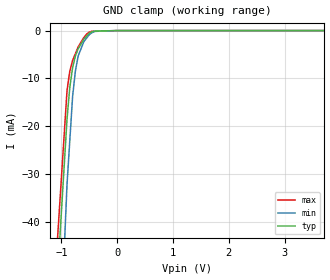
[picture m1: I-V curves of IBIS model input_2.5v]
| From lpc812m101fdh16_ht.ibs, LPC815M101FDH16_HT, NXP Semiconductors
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[Model] input_2.5v
Model_type Input
Vinl = 750.000mV
Vinh = 1.75000V
C_comp 909.000fF 904.000fF 914.000fF
| variable typ   min   max
[Voltage Range] 2.50000V 2.25000V 2.75000V
[POWER Clamp Reference] 2.50000V 2.25000V 2.75000V
[GND Clamp Reference] 0.00000V 0.00000V 0.00000V
[Temperature Range]   25   105   -40
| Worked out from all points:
|   GND clamp passes 1 mA (typ) near -0.54 V on its own axis
[GND Clamp]
-2.5V     -327.3mA   -468.3mA   -303.5mA
-900mV    -18.53mA   -32.17mA   -12.56mA
-850mV    -11.85mA   -22.98mA   -8.473mA
-800mV    -7.74mA    -13.78mA   -6.254mA
-750mV    -5.325mA   -8.465mA   -4.829mA
-700mV    -3.812mA   -5.309mA   -3.403mA
-600mV    -1.827mA   -2.349mA   -1.457mA
-550mV    -1.183mA   -1.595mA   -748.6uA
-500mV    -537.7uA   -841.1uA   -319uA
-400mV    -100.7uA   -173uA     -124uA
0V        0A         0A         0A
5V        0A         0A         0A
[POWER Clamp]
-2.5V     0A         0A         0A
5V        0A         0A         0A
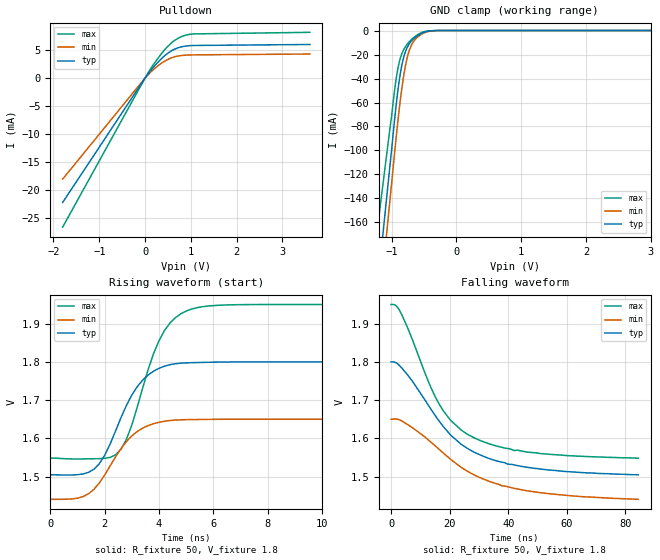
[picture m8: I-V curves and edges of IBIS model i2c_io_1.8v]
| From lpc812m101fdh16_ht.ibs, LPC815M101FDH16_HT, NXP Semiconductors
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[Model]   i2c_io_1.8v
Model_type I/O_open_drain
Vinl=5.400E-01
Vinh=1.260E+00
Vref=1.800E+00
Rref=1.000E+03
Cref=0.000E+00
Vmeas=9.000E-01
C_comp   1.060E-12   9.990E-13   1.120E-12
[Voltage Range]   1.800E+00   1.650E+00   1.950E+00
[POWER Clamp Reference]   1.800E+00   1.650E+00   1.950E+00
[GND Clamp Reference]   0.000E+00   0.000E+00   0.000E+00
[Pullup Reference]   1.800E+00   1.650E+00   1.950E+00
[Pulldown Reference]   0.000E+00   0.000E+00   0.000E+00
[Temperature Range]   25   105   -40
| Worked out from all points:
|   slope of the pulldown table from 0 to 0.27 V, typ, clamps not added: 98.8 ohm
|   GND clamp passes 1 mA (typ) near -0.47 V on its own axis
|   rising waveform, R_fixture 50, V_fixture 1.8: 20-80 % time 1.21ns typ, 1.23ns min, 1.14ns max; typ from 1.5 V to 1.8 V
|   falling waveform, R_fixture 50, V_fixture 1.8: 20-80 % time 20.3ns typ, 24.8ns min, 16.3ns max; typ from 1.8 V to 1.5 V
[GND Clamp]
-1.8V     -519.6mA   -563.5mA   -415.2mA
-1.02V    -109.2mA   -137.9mA   -78.79mA
-940mV    -66.79mA   -94.14mA   -43.75mA
-900mV    -48.42mA   -73.59mA   -30.61mA
-860mV    -33.9mA    -55.2mA    -21.96mA
-800mV    -19.64mA   -33.09mA   -14.6mA
-760mV    -14.12mA   -22.67mA   -11.43mA
-700mV    -9.08mA    -12.83mA   -7.792mA
-640mV    -5.959mA   -7.675mA   -5.035mA
-560mV    -2.946mA   -3.834mA   -2.215mA
-280mV    0A         0A         0A
3.6V      0A         0A         0A
[Pulldown]
-1.8V     -22.3mA    -18.12mA   -26.72mA
20mV      229.7uA    181.9uA    281.2uA
180mV     1.925mA    1.5mA      2.384mA
360mV     3.492mA    2.67mA     4.395mA
480mV     4.341mA    3.271mA    5.534mA
600mV     4.992mA    3.699mA    6.458mA
800mV     5.611mA    4.048mA    7.447mA
1.06V     5.842mA    4.156mA    7.913mA
3.6V      6.016mA    4.309mA    8.197mA
[Rising Waveform]
R_fixture = 50
V_fixture = 1.8
V_fixture_min = 1.65
V_fixture_max = 1.95
0s        1.505V     1.441V     1.548V
1ns       1.505V     1.444V     1.546V
1.6ns     1.519V     1.467V     1.547V
2ns       1.556V     1.504V     1.548V
2.6ns     1.654V     1.573V     1.572V
3.2ns     1.735V     1.618V     1.682V
4ns       1.783V     1.642V     1.856V
4.6ns     1.795V     1.648V     1.915V
5.2ns     1.798V     1.649V     1.938V
16.4ns    1.8V       1.65V      1.95V
[Falling Waveform]
R_fixture = 50
V_fixture = 1.8
V_fixture_min = 1.65
V_fixture_max = 1.95
0s        1.8V       1.65V      1.95V
1.8ns     1.797V     1.651V     1.946V
3.6ns     1.785V     1.646V     1.924V
13ns      1.683V     1.594V     1.744V
16.6ns    1.643V     1.57V      1.687V
20.6ns    1.607V     1.544V     1.645V
25.8ns    1.575V     1.515V     1.612V
33.6ns    1.547V     1.487V     1.586V
42ns      1.531V     1.47V      1.568V
84.4ns    1.505V     1.441V     1.548V
[Ramp]
dV/dt_r   1.7711E-01/1.1990E-09   1.2559E-01/1.2320E-09   2.4097E-01/1.1310E-09
dV/dt_f   1.7711E-01/2.0316E-08   1.2559E-01/2.4662E-08   2.4097E-01/1.6172E-08
R_load = 50
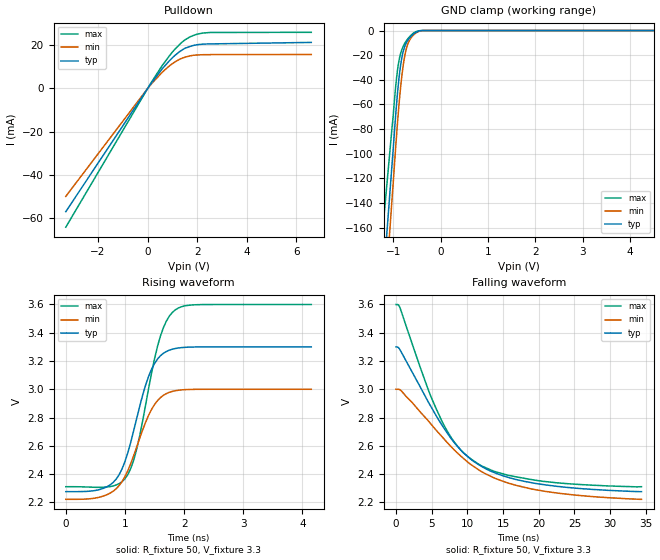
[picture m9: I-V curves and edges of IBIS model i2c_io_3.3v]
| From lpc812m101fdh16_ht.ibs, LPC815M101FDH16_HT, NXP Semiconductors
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[Model]   i2c_io_3.3v
Model_type I/O_open_drain
Vinl=9.900E-01
Vinh=2.310E+00
Vref=3.300E+00
Rref=1.000E+03
Cref=0.000E+00
Vmeas=1.650E+00
C_comp   1.060E-12   9.990E-13   1.120E-12
[Voltage Range]   3.300E+00   3.000E+00   3.600E+00
[POWER Clamp Reference]   3.300E+00   3.000E+00   3.600E+00
[GND Clamp Reference]   0.000E+00   0.000E+00   0.000E+00
[Pullup Reference]   3.300E+00   3.000E+00   3.600E+00
[Pulldown Reference]   0.000E+00   0.000E+00   0.000E+00
[Temperature Range]   25   105   -40
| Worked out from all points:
|   slope of the pulldown table from 0 to 0.495 V, typ, clamps not added: 64 ohm
|   GND clamp passes 1 mA (typ) near -0.50 V on its own axis
|   rising waveform, R_fixture 50, V_fixture 3.3: 20-80 % time 411ps typ, 441ps min, 383ps max; typ from 2.28 V to 3.3 V
|   falling waveform, R_fixture 50, V_fixture 3.3: 20-80 % time 8.61ns typ, 10.3ns min, 6.98ns max; typ from 3.3 V to 2.28 V
[GND Clamp]
-3.3V     -1.272A    -1.374A    -1.043A
-1.02V    -106.2mA   -134.5mA   -76.92mA
-940mV    -64.97mA   -90.81mA   -42.49mA
-900mV    -47.07mA   -70.46mA   -29.59mA
-840mV    -27.19mA   -44.76mA   -18.14mA
-780mV    -15.75mA   -26.03mA   -12.16mA
-740mV    -11.34mA   -17.58mA   -9.414mA
-680mV    -7.232mA   -9.814mA   -6.185mA
-620mV    -4.56mA    -5.746mA   -3.706mA
-520mV    -1.426mA   -1.973mA   -922uA
-380mV    0A         0A         0A
6.6V      0A         0A         0A
[Pulldown]
-3.3V     -57.19mA   -50.1mA    -64.4mA
140mV     2.326mA    1.953mA    2.677mA
560mV     8.72mA     7.204mA    10.16mA
920mV     13.36mA    10.86mA    15.8mA
1.1V      15.38mA    12.32mA    18.22mA
1.48V     18.52mA    14.45mA    22.35mA
1.7V      19.47mA    15.11mA    23.91mA
2V        20.34mA    15.58mA    25.25mA
2.54V     20.71mA    15.73mA    26.03mA
6.6V      21.4mA     15.79mA    26.09mA
[Rising Waveform]
R_fixture = 50
V_fixture = 3.3
V_fixture_min = 3
V_fixture_max = 3.6
0s        2.276V     2.221V     2.31V
750ps     2.324V     2.265V     2.311V
900ps     2.394V     2.317V     2.332V
1.05ns    2.553V     2.426V     2.397V
1.2ns     2.796V     2.593V     2.579V
1.45ns    3.142V     2.858V     3.116V
1.65ns    3.255V     2.957V     3.436V
1.85ns    3.288V     2.99V      3.562V
2.2ns     3.299V     2.999V     3.598V
4.15ns    3.3V       3V         3.6V
[Falling Waveform]
R_fixture = 50
V_fixture = 3.3
V_fixture_min = 3
V_fixture_max = 3.6
0s        3.3V       3V         3.6V
550ps     3.281V     2.997V     3.579V
4.5ns     2.912V     2.778V     3V
6.45ns    2.745V     2.664V     2.773V
8.25ns    2.617V     2.567V     2.621V
10.3ns    2.513V     2.475V     2.514V
13.7ns    2.412V     2.374V     2.42V
18.1ns    2.347V     2.305V     2.369V
24.65ns   2.302V     2.253V     2.33V
34.4ns    2.276V     2.221V     2.31V
[Ramp]
dV/dt_r   6.1467E-01/4.0990E-10   4.6738E-01/4.3930E-10   7.7377E-01/3.8130E-10
dV/dt_f   6.1467E-01/8.5863E-09   4.6738E-01/1.0265E-08   7.7377E-01/6.9793E-09
R_load = 50
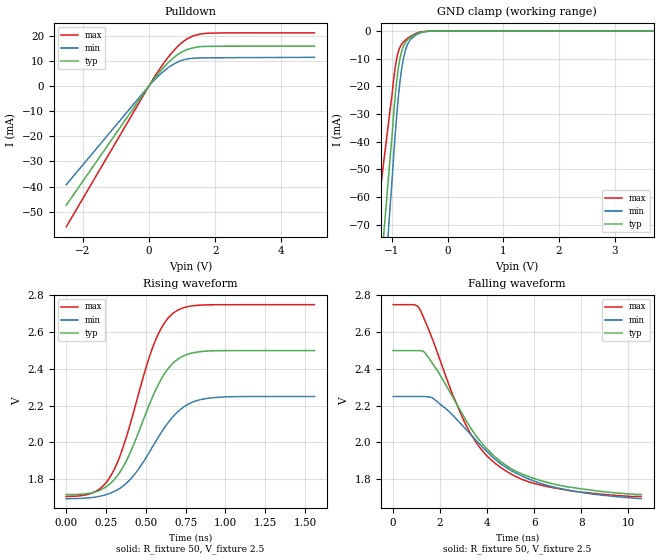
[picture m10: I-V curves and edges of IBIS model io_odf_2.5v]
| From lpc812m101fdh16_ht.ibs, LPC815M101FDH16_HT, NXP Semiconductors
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[Model]   io_odf_2.5v
Model_type I/O_open_drain
Vinl=7.500E-01
Vinh=1.750E+00
Vref=2.500E+00
Rref=1.000E+03
Cref=2.000E-11
Vmeas=1.250E+00
C_comp   6.740E-13   6.620E-13   6.860E-13
[Voltage Range]   2.500E+00   2.250E+00   2.750E+00
[POWER Clamp Reference]   2.500E+00   2.250E+00   2.750E+00
[GND Clamp Reference]   0.000E+00   0.000E+00   0.000E+00
[Pullup Reference]   2.500E+00   2.250E+00   2.750E+00
[Pulldown Reference]   0.000E+00   0.000E+00   0.000E+00
[Temperature Range]   25   105   -40
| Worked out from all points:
|   slope of the pulldown table from 0 to 0.375 V, typ, clamps not added: 59.6 ohm
|   GND clamp passes 1 mA (typ) near -0.55 V on its own axis
|   rising waveform, R_fixture 50, V_fixture 2.5: 20-80 % time 234ps typ, 261ps min, 222ps max; typ from 1.72 V to 2.5 V
|   falling waveform, R_fixture 50, V_fixture 2.5: 20-80 % time 2.72ns typ, 3.09ns min, 2.36ns max; typ from 2.5 V to 1.72 V
[GND Clamp]
-2.5V     -400.8mA   -480.7mA   -270.8mA
-1.02V    -43.1mA    -60.31mA   -26.6mA
-1V       -38.68mA   -54.9mA    -23.79mA
-960mV    -28.15mA   -42.98mA   -16.18mA
-920mV    -19.39mA   -32.21mA   -10.63mA
-880mV    -12.91mA   -23.14mA   -7.24mA
-820mV    -7.048mA   -13.16mA   -4.672mA
-780mV    -4.938mA   -8.808mA   -3.728mA
-720mV    -3.192mA   -4.874mA   -2.627mA
-580mV    -1.272mA   -1.617mA   -998.7uA
-300mV    0A         0A         0A
5V        0A         0A         0A
[Pulldown]
-2.5V     -47.41mA   -39.28mA   -56.02mA
120mV     2.161mA    1.747mA    2.601mA
580mV     9.226mA    7.226mA    11.39mA
840mV     12.16mA    9.303mA    15.31mA
1.06V     13.92mA    10.4mA     17.85mA
1.38V     15.21mA    11.01mA    20.05mA
1.76V     15.68mA    11.14mA    20.93mA
5V        15.77mA    11.36mA    21.08mA
[Rising Waveform]
R_fixture = 50
V_fixture = 2.5
V_fixture_min = 2.25
V_fixture_max = 2.75
0s        1.717V     1.694V     1.706V
180ps     1.73V      1.702V     1.731V
280ps     1.779V     1.725V     1.818V
380ps     1.903V     1.779V     2.035V
560ps     2.282V     2.002V     2.554V
620ps     2.377V     2.084V     2.654V
680ps     2.439V     2.149V     2.709V
780ps     2.484V     2.214V     2.742V
900ps     2.498V     2.241V     2.749V
1.56ns    2.5V       2.25V      2.75V
[Falling Waveform]
R_fixture = 50
V_fixture = 2.5
V_fixture_min = 2.25
V_fixture_max = 2.75
0s        2.5V       2.25V      2.75V
1.1ns     2.5V       2.25V      2.733V
1.34ns    2.49V      2.25V      2.667V
1.7ns     2.426V     2.24V      2.554V
3.02ns    2.138V     2.082V     2.115V
3.64ns    2.017V     1.997V     1.98V
4.4ns     1.915V     1.902V     1.881V
5.46ns    1.829V     1.818V     1.8V
6.66ns    1.779V     1.763V     1.757V
10.56ns   1.717V     1.694V     1.706V
[Ramp]
dV/dt_r   4.7003E-01/2.3420E-10   3.3371E-01/2.6010E-10   6.2651E-01/2.2120E-10
dV/dt_f   4.7003E-01/2.7127E-09   3.3371E-01/3.0825E-09   6.2651E-01/2.3493E-09
R_load = 50
